VERSION 5.7 ;
  NOWIREEXTENSIONATPIN ON ;
  DIVIDERCHAR "/" ;
  BUSBITCHARS "[]" ;
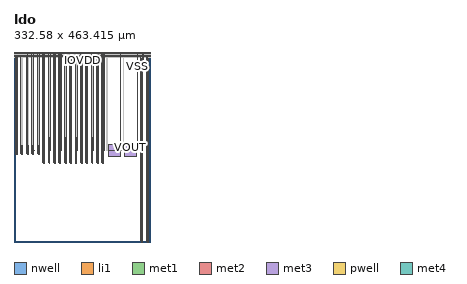
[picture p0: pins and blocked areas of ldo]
MACRO ldo
  CLASS BLOCK ;
  FOREIGN ldo ;
  ORIGIN 4.500 223.305 ;
  SIZE 332.580 BY 463.415 ;
  PIN IOVDD
    DIRECTION INOUT ;
    USE POWER ;
    ANTENNADIFFAREA 494.460388 ;
    PORT
      LAYER nwell ;
        RECT 40.880 -11.095 43.340 11.095 ;
        RECT 54.340 -11.095 56.800 11.095 ;
        RECT 67.800 -31.095 69.910 31.095 ;
        RECT 80.910 -31.095 83.020 31.095 ;
        RECT 94.020 -31.095 96.130 31.095 ;
        RECT 107.130 -31.095 109.240 31.095 ;
        RECT 120.240 -31.095 122.350 31.095 ;
        RECT 133.350 -31.095 135.460 31.095 ;
        RECT 146.460 -31.095 148.570 31.095 ;
        RECT 159.570 -31.095 161.680 31.095 ;
        RECT 172.680 -31.095 174.790 31.095 ;
        RECT 185.790 -31.095 187.900 31.095 ;
        RECT 198.900 -31.095 201.010 31.095 ;
        RECT 212.010 -31.095 214.120 31.095 ;
      LAYER li1 ;
        RECT 67.980 30.745 69.730 30.915 ;
        RECT 41.060 10.745 43.160 10.915 ;
        RECT 41.060 -7.685 41.230 10.745 ;
        RECT 38.880 -8.185 41.230 -7.685 ;
        RECT 41.060 -10.745 41.230 -8.185 ;
        RECT 42.420 -10.020 42.590 10.020 ;
        RECT 42.990 -10.745 43.160 10.745 ;
        RECT 54.520 10.745 56.620 10.915 ;
        RECT 54.520 -7.685 54.690 10.745 ;
        RECT 52.340 -8.185 54.690 -7.685 ;
        RECT 41.060 -10.915 43.160 -10.745 ;
        RECT 54.520 -10.745 54.690 -8.185 ;
        RECT 55.880 -10.020 56.050 10.020 ;
        RECT 56.450 -10.745 56.620 10.745 ;
        RECT 54.520 -10.915 56.620 -10.745 ;
        RECT 67.980 -27.685 68.150 30.745 ;
        RECT 65.800 -28.185 68.150 -27.685 ;
        RECT 67.980 -30.745 68.150 -28.185 ;
        RECT 68.990 -30.020 69.160 30.020 ;
        RECT 69.560 -30.745 69.730 30.745 ;
        RECT 81.090 30.745 82.840 30.915 ;
        RECT 81.090 -27.685 81.260 30.745 ;
        RECT 78.910 -28.185 81.260 -27.685 ;
        RECT 67.980 -30.915 69.730 -30.745 ;
        RECT 81.090 -30.745 81.260 -28.185 ;
        RECT 82.100 -30.020 82.270 30.020 ;
        RECT 82.670 -30.745 82.840 30.745 ;
        RECT 94.200 30.745 95.950 30.915 ;
        RECT 94.200 -27.685 94.370 30.745 ;
        RECT 92.020 -28.185 94.370 -27.685 ;
        RECT 81.090 -30.915 82.840 -30.745 ;
        RECT 94.200 -30.745 94.370 -28.185 ;
        RECT 95.210 -30.020 95.380 30.020 ;
        RECT 95.780 -30.745 95.950 30.745 ;
        RECT 107.310 30.745 109.060 30.915 ;
        RECT 107.310 -27.685 107.480 30.745 ;
        RECT 105.130 -28.185 107.480 -27.685 ;
        RECT 94.200 -30.915 95.950 -30.745 ;
        RECT 107.310 -30.745 107.480 -28.185 ;
        RECT 108.320 -30.020 108.490 30.020 ;
        RECT 108.890 -30.745 109.060 30.745 ;
        RECT 120.420 30.745 122.170 30.915 ;
        RECT 120.420 -27.685 120.590 30.745 ;
        RECT 118.240 -28.185 120.590 -27.685 ;
        RECT 107.310 -30.915 109.060 -30.745 ;
        RECT 120.420 -30.745 120.590 -28.185 ;
        RECT 121.430 -30.020 121.600 30.020 ;
        RECT 122.000 -30.745 122.170 30.745 ;
        RECT 133.530 30.745 135.280 30.915 ;
        RECT 133.530 -27.685 133.700 30.745 ;
        RECT 131.350 -28.185 133.700 -27.685 ;
        RECT 120.420 -30.915 122.170 -30.745 ;
        RECT 133.530 -30.745 133.700 -28.185 ;
        RECT 134.540 -30.020 134.710 30.020 ;
        RECT 135.110 -30.745 135.280 30.745 ;
        RECT 146.640 30.745 148.390 30.915 ;
        RECT 146.640 -27.685 146.810 30.745 ;
        RECT 144.460 -28.185 146.810 -27.685 ;
        RECT 133.530 -30.915 135.280 -30.745 ;
        RECT 146.640 -30.745 146.810 -28.185 ;
        RECT 147.650 -30.020 147.820 30.020 ;
        RECT 148.220 -30.745 148.390 30.745 ;
        RECT 159.750 30.745 161.500 30.915 ;
        RECT 159.750 -27.685 159.920 30.745 ;
        RECT 157.570 -28.185 159.920 -27.685 ;
        RECT 146.640 -30.915 148.390 -30.745 ;
        RECT 159.750 -30.745 159.920 -28.185 ;
        RECT 160.760 -30.020 160.930 30.020 ;
        RECT 161.330 -30.745 161.500 30.745 ;
        RECT 172.860 30.745 174.610 30.915 ;
        RECT 172.860 -27.685 173.030 30.745 ;
        RECT 170.680 -28.185 173.030 -27.685 ;
        RECT 159.750 -30.915 161.500 -30.745 ;
        RECT 172.860 -30.745 173.030 -28.185 ;
        RECT 173.870 -30.020 174.040 30.020 ;
        RECT 174.440 -30.745 174.610 30.745 ;
        RECT 185.970 30.745 187.720 30.915 ;
        RECT 185.970 -27.685 186.140 30.745 ;
        RECT 183.790 -28.185 186.140 -27.685 ;
        RECT 172.860 -30.915 174.610 -30.745 ;
        RECT 185.970 -30.745 186.140 -28.185 ;
        RECT 186.980 -30.020 187.150 30.020 ;
        RECT 187.550 -30.745 187.720 30.745 ;
        RECT 199.080 30.745 200.830 30.915 ;
        RECT 199.080 -27.685 199.250 30.745 ;
        RECT 196.900 -28.185 199.250 -27.685 ;
        RECT 185.970 -30.915 187.720 -30.745 ;
        RECT 199.080 -30.745 199.250 -28.185 ;
        RECT 200.090 -30.020 200.260 30.020 ;
        RECT 200.660 -30.745 200.830 30.745 ;
        RECT 212.190 30.745 213.940 30.915 ;
        RECT 212.190 -27.685 212.360 30.745 ;
        RECT 210.010 -28.185 212.360 -27.685 ;
        RECT 199.080 -30.915 200.830 -30.745 ;
        RECT 212.190 -30.745 212.360 -28.185 ;
        RECT 213.200 -30.020 213.370 30.020 ;
        RECT 213.770 -30.745 213.940 30.745 ;
        RECT 212.190 -30.915 213.940 -30.745 ;
      LAYER met1 ;
        RECT 42.390 0.200 42.620 10.000 ;
        RECT 55.850 0.200 56.080 10.000 ;
        RECT 68.960 0.200 69.190 30.000 ;
        RECT 82.070 0.200 82.300 30.000 ;
        RECT 95.180 0.200 95.410 30.000 ;
        RECT 108.290 0.200 108.520 30.000 ;
        RECT 121.400 0.200 121.630 30.000 ;
        RECT 134.510 0.200 134.740 30.000 ;
        RECT 147.620 0.200 147.850 30.000 ;
        RECT 160.730 0.200 160.960 30.000 ;
        RECT 173.840 0.200 174.070 30.000 ;
        RECT 186.950 0.200 187.180 30.000 ;
        RECT 200.060 0.200 200.290 30.000 ;
        RECT 213.170 0.200 213.400 30.000 ;
        RECT 42.390 -0.200 44.290 0.200 ;
        RECT 55.850 -0.200 57.750 0.200 ;
        RECT 68.960 -0.200 70.860 0.200 ;
        RECT 82.070 -0.200 83.970 0.200 ;
        RECT 95.180 -0.200 97.080 0.200 ;
        RECT 108.290 -0.200 110.190 0.200 ;
        RECT 121.400 -0.200 123.300 0.200 ;
        RECT 134.510 -0.200 136.410 0.200 ;
        RECT 147.620 -0.200 149.520 0.200 ;
        RECT 160.730 -0.200 162.630 0.200 ;
        RECT 173.840 -0.200 175.740 0.200 ;
        RECT 186.950 -0.200 188.850 0.200 ;
        RECT 200.060 -0.200 201.960 0.200 ;
        RECT 213.170 -0.200 215.070 0.200 ;
        RECT 38.930 -8.135 39.330 -7.735 ;
        RECT 42.390 -10.000 42.620 -0.200 ;
        RECT 52.390 -8.135 52.790 -7.735 ;
        RECT 55.850 -10.000 56.080 -0.200 ;
        RECT 65.850 -28.135 66.250 -27.735 ;
        RECT 68.960 -30.000 69.190 -0.200 ;
        RECT 78.960 -28.135 79.360 -27.735 ;
        RECT 82.070 -30.000 82.300 -0.200 ;
        RECT 92.070 -28.135 92.470 -27.735 ;
        RECT 95.180 -30.000 95.410 -0.200 ;
        RECT 105.180 -28.135 105.580 -27.735 ;
        RECT 108.290 -30.000 108.520 -0.200 ;
        RECT 118.290 -28.135 118.690 -27.735 ;
        RECT 121.400 -30.000 121.630 -0.200 ;
        RECT 131.400 -28.135 131.800 -27.735 ;
        RECT 134.510 -30.000 134.740 -0.200 ;
        RECT 144.510 -28.135 144.910 -27.735 ;
        RECT 147.620 -30.000 147.850 -0.200 ;
        RECT 157.620 -28.135 158.020 -27.735 ;
        RECT 160.730 -30.000 160.960 -0.200 ;
        RECT 170.730 -28.135 171.130 -27.735 ;
        RECT 173.840 -30.000 174.070 -0.200 ;
        RECT 183.840 -28.135 184.240 -27.735 ;
        RECT 186.950 -30.000 187.180 -0.200 ;
        RECT 196.950 -28.135 197.350 -27.735 ;
        RECT 200.060 -30.000 200.290 -0.200 ;
        RECT 210.060 -28.135 210.460 -27.735 ;
        RECT 213.170 -30.000 213.400 -0.200 ;
      LAYER met2 ;
        RECT 38.930 238.160 39.330 238.560 ;
        RECT 43.890 238.160 44.290 238.560 ;
        RECT 52.390 238.160 52.790 238.560 ;
        RECT 57.350 238.160 57.750 238.560 ;
        RECT 65.850 238.160 66.250 238.560 ;
        RECT 70.460 238.160 70.860 238.560 ;
        RECT 78.960 238.160 79.360 238.560 ;
        RECT 83.570 238.160 83.970 238.560 ;
        RECT 92.070 238.160 92.470 238.560 ;
        RECT 96.680 238.160 97.080 238.560 ;
        RECT 105.180 238.160 105.580 238.560 ;
        RECT 109.790 238.160 110.190 238.560 ;
        RECT 118.290 238.160 118.690 238.560 ;
        RECT 122.900 238.160 123.300 238.560 ;
        RECT 131.400 238.160 131.800 238.560 ;
        RECT 136.010 238.160 136.410 238.560 ;
        RECT 144.510 238.160 144.910 238.560 ;
        RECT 149.120 238.160 149.520 238.560 ;
        RECT 157.620 238.160 158.020 238.560 ;
        RECT 162.230 238.160 162.630 238.560 ;
        RECT 170.730 238.160 171.130 238.560 ;
        RECT 175.340 238.160 175.740 238.560 ;
        RECT 183.840 238.160 184.240 238.560 ;
        RECT 188.450 238.160 188.850 238.560 ;
        RECT 196.950 238.160 197.350 238.560 ;
        RECT 201.560 238.160 201.960 238.560 ;
        RECT 210.060 238.160 210.460 238.560 ;
        RECT 214.670 238.160 215.070 238.560 ;
        RECT 38.980 -7.735 39.280 238.160 ;
        RECT 43.940 0.200 44.240 238.160 ;
        RECT 43.890 -0.200 44.290 0.200 ;
        RECT 52.440 -7.735 52.740 238.160 ;
        RECT 57.400 0.200 57.700 238.160 ;
        RECT 57.350 -0.200 57.750 0.200 ;
        RECT 38.930 -8.135 39.330 -7.735 ;
        RECT 52.390 -8.135 52.790 -7.735 ;
        RECT 65.900 -27.735 66.200 238.160 ;
        RECT 70.510 0.200 70.810 238.160 ;
        RECT 70.460 -0.200 70.860 0.200 ;
        RECT 79.010 -27.735 79.310 238.160 ;
        RECT 83.620 0.200 83.920 238.160 ;
        RECT 83.570 -0.200 83.970 0.200 ;
        RECT 92.120 -27.735 92.420 238.160 ;
        RECT 96.730 0.200 97.030 238.160 ;
        RECT 96.680 -0.200 97.080 0.200 ;
        RECT 105.230 -27.735 105.530 238.160 ;
        RECT 109.840 0.200 110.140 238.160 ;
        RECT 109.790 -0.200 110.190 0.200 ;
        RECT 118.340 -27.735 118.640 238.160 ;
        RECT 122.950 0.200 123.250 238.160 ;
        RECT 122.900 -0.200 123.300 0.200 ;
        RECT 131.450 -27.735 131.750 238.160 ;
        RECT 136.060 0.200 136.360 238.160 ;
        RECT 136.010 -0.200 136.410 0.200 ;
        RECT 144.560 -27.735 144.860 238.160 ;
        RECT 149.170 0.200 149.470 238.160 ;
        RECT 149.120 -0.200 149.520 0.200 ;
        RECT 157.670 -27.735 157.970 238.160 ;
        RECT 162.280 0.200 162.580 238.160 ;
        RECT 162.230 -0.200 162.630 0.200 ;
        RECT 170.780 -27.735 171.080 238.160 ;
        RECT 175.390 0.200 175.690 238.160 ;
        RECT 175.340 -0.200 175.740 0.200 ;
        RECT 183.890 -27.735 184.190 238.160 ;
        RECT 188.500 0.200 188.800 238.160 ;
        RECT 188.450 -0.200 188.850 0.200 ;
        RECT 197.000 -27.735 197.300 238.160 ;
        RECT 201.610 0.200 201.910 238.160 ;
        RECT 201.560 -0.200 201.960 0.200 ;
        RECT 210.110 -27.735 210.410 238.160 ;
        RECT 214.720 0.200 215.020 238.160 ;
        RECT 214.670 -0.200 215.070 0.200 ;
        RECT 65.850 -28.135 66.250 -27.735 ;
        RECT 78.960 -28.135 79.360 -27.735 ;
        RECT 92.070 -28.135 92.470 -27.735 ;
        RECT 105.180 -28.135 105.580 -27.735 ;
        RECT 118.290 -28.135 118.690 -27.735 ;
        RECT 131.400 -28.135 131.800 -27.735 ;
        RECT 144.510 -28.135 144.910 -27.735 ;
        RECT 157.620 -28.135 158.020 -27.735 ;
        RECT 170.730 -28.135 171.130 -27.735 ;
        RECT 183.840 -28.135 184.240 -27.735 ;
        RECT 196.950 -28.135 197.350 -27.735 ;
        RECT 210.060 -28.135 210.460 -27.735 ;
      LAYER met3 ;
        RECT -4.500 238.110 328.080 238.610 ;
    END
  END IOVDD
  PIN VSS
    DIRECTION INOUT ;
    USE GROUND ;
    ANTENNADIFFAREA 332.556396 ;
    PORT
      LAYER pwell ;
        RECT 0.000 -9.050 2.960 9.050 ;
        RECT 13.960 -11.050 16.420 11.050 ;
        RECT 27.420 -11.050 29.880 11.050 ;
        RECT 306.440 -223.360 309.510 223.360 ;
        RECT 320.510 -223.360 323.580 223.360 ;
      LAYER li1 ;
        RECT 306.620 223.010 309.330 223.180 ;
        RECT 14.140 10.700 16.240 10.870 ;
        RECT 0.180 8.700 2.780 8.870 ;
        RECT 0.180 -5.640 0.350 8.700 ;
        RECT -2.000 -6.140 0.350 -5.640 ;
        RECT 0.180 -8.700 0.350 -6.140 ;
        RECT 2.040 -8.020 2.210 8.020 ;
        RECT 2.610 -8.700 2.780 8.700 ;
        RECT 14.140 -7.640 14.310 10.700 ;
        RECT 11.960 -8.140 14.310 -7.640 ;
        RECT 0.180 -8.870 2.780 -8.700 ;
        RECT 14.140 -10.700 14.310 -8.140 ;
        RECT 16.070 -10.700 16.240 10.700 ;
        RECT 27.600 10.700 29.700 10.870 ;
        RECT 27.600 -7.640 27.770 10.700 ;
        RECT 25.420 -8.140 27.770 -7.640 ;
        RECT 14.140 -10.870 16.240 -10.700 ;
        RECT 27.600 -10.700 27.770 -8.140 ;
        RECT 29.530 -10.700 29.700 10.700 ;
        RECT 27.600 -10.870 29.700 -10.700 ;
        RECT 306.620 -219.950 306.790 223.010 ;
        RECT 304.440 -220.450 306.790 -219.950 ;
        RECT 306.620 -223.010 306.790 -220.450 ;
        RECT 309.160 -223.010 309.330 223.010 ;
        RECT 320.690 223.010 323.400 223.180 ;
        RECT 320.690 -219.950 320.860 223.010 ;
        RECT 318.510 -220.450 320.860 -219.950 ;
        RECT 306.620 -223.180 309.330 -223.010 ;
        RECT 320.690 -223.010 320.860 -220.450 ;
        RECT 321.340 -222.530 322.750 -220.370 ;
        RECT 323.230 -223.010 323.400 223.010 ;
        RECT 320.690 -223.180 323.400 -223.010 ;
      LAYER met1 ;
        RECT 2.010 0.200 2.240 8.000 ;
        RECT 2.010 -0.200 3.910 0.200 ;
        RECT -1.950 -6.090 -1.550 -5.690 ;
        RECT 2.010 -8.000 2.240 -0.200 ;
        RECT 12.010 -8.090 12.410 -7.690 ;
        RECT 25.470 -8.090 25.870 -7.690 ;
        RECT 304.490 -220.400 304.890 -220.000 ;
        RECT 318.560 -220.400 318.960 -220.000 ;
        RECT 321.390 -222.155 322.700 -220.395 ;
        RECT 319.560 -222.500 322.700 -222.155 ;
        RECT 319.560 -222.555 322.045 -222.500 ;
      LAYER met2 ;
        RECT -1.950 230.660 -1.550 231.060 ;
        RECT 3.510 230.660 3.910 231.060 ;
        RECT 12.010 230.660 12.410 231.060 ;
        RECT 25.470 230.660 25.870 231.060 ;
        RECT 304.490 230.660 304.890 231.060 ;
        RECT 318.560 230.660 318.960 231.060 ;
        RECT 319.560 230.660 319.960 231.060 ;
        RECT -1.900 -5.690 -1.600 230.660 ;
        RECT 3.560 0.200 3.860 230.660 ;
        RECT 3.510 -0.200 3.910 0.200 ;
        RECT -1.950 -6.090 -1.550 -5.690 ;
        RECT 12.060 -7.690 12.360 230.660 ;
        RECT 25.520 -7.690 25.820 230.660 ;
        RECT 12.010 -8.090 12.410 -7.690 ;
        RECT 25.470 -8.090 25.870 -7.690 ;
        RECT 304.540 -220.000 304.840 230.660 ;
        RECT 318.610 -220.000 318.910 230.660 ;
        RECT 304.490 -220.400 304.890 -220.000 ;
        RECT 318.560 -220.400 318.960 -220.000 ;
        RECT 319.610 -222.155 319.910 230.660 ;
        RECT 319.560 -222.555 319.960 -222.155 ;
      LAYER met3 ;
        RECT -4.500 230.610 328.080 231.110 ;
    END
  END VSS
  PIN VREF
    DIRECTION INPUT ;
    USE SIGNAL ;
    ANTENNAGATEAREA 10.000000 ;
    PORT
      LAYER li1 ;
        RECT 28.400 10.190 28.900 10.360 ;
        RECT 28.400 -10.360 28.900 -10.190 ;
      LAYER met1 ;
        RECT 28.450 10.390 28.850 10.725 ;
        RECT 28.420 10.160 28.880 10.390 ;
        RECT 28.420 -10.390 28.880 -10.160 ;
        RECT 28.450 -10.725 28.850 -10.390 ;
      LAYER met2 ;
        RECT 28.450 236.660 28.850 237.060 ;
        RECT 28.500 10.675 28.800 236.660 ;
        RECT 28.450 10.275 28.850 10.675 ;
      LAYER met3 ;
        RECT -4.500 236.610 328.080 237.110 ;
    END
  END VREF
  PIN VOUT
    DIRECTION OUTPUT ;
    USE SIGNAL ;
    ANTENNADIFFAREA 208.799988 ;
    PORT
      LAYER li1 ;
        RECT 307.270 220.370 308.680 222.530 ;
        RECT 68.550 -30.020 68.720 30.020 ;
        RECT 81.660 -30.020 81.830 30.020 ;
        RECT 94.770 -30.020 94.940 30.020 ;
        RECT 107.880 -30.020 108.050 30.020 ;
        RECT 120.990 -30.020 121.160 30.020 ;
        RECT 134.100 -30.020 134.270 30.020 ;
        RECT 147.210 -30.020 147.380 30.020 ;
        RECT 160.320 -30.020 160.490 30.020 ;
        RECT 173.430 -30.020 173.600 30.020 ;
        RECT 186.540 -30.020 186.710 30.020 ;
        RECT 199.650 -30.020 199.820 30.020 ;
        RECT 212.760 -30.020 212.930 30.020 ;
      LAYER met1 ;
        RECT 307.975 222.500 310.460 222.555 ;
        RECT 307.320 222.155 310.460 222.500 ;
        RECT 307.320 220.395 308.630 222.155 ;
        RECT 68.520 0.200 68.750 30.000 ;
        RECT 81.630 0.200 81.860 30.000 ;
        RECT 94.740 0.200 94.970 30.000 ;
        RECT 107.850 0.200 108.080 30.000 ;
        RECT 120.960 0.200 121.190 30.000 ;
        RECT 134.070 0.200 134.300 30.000 ;
        RECT 147.180 0.200 147.410 30.000 ;
        RECT 160.290 0.200 160.520 30.000 ;
        RECT 173.400 0.200 173.630 30.000 ;
        RECT 186.510 0.200 186.740 30.000 ;
        RECT 199.620 0.200 199.850 30.000 ;
        RECT 212.730 0.200 212.960 30.000 ;
        RECT 66.850 -0.200 68.750 0.200 ;
        RECT 79.960 -0.200 81.860 0.200 ;
        RECT 93.070 -0.200 94.970 0.200 ;
        RECT 106.180 -0.200 108.080 0.200 ;
        RECT 119.290 -0.200 121.190 0.200 ;
        RECT 132.400 -0.200 134.300 0.200 ;
        RECT 145.510 -0.200 147.410 0.200 ;
        RECT 158.620 -0.200 160.520 0.200 ;
        RECT 171.730 -0.200 173.630 0.200 ;
        RECT 184.840 -0.200 186.740 0.200 ;
        RECT 197.950 -0.200 199.850 0.200 ;
        RECT 211.060 -0.200 212.960 0.200 ;
        RECT 68.520 -30.000 68.750 -0.200 ;
        RECT 81.630 -30.000 81.860 -0.200 ;
        RECT 94.740 -30.000 94.970 -0.200 ;
        RECT 107.850 -30.000 108.080 -0.200 ;
        RECT 120.960 -30.000 121.190 -0.200 ;
        RECT 134.070 -30.000 134.300 -0.200 ;
        RECT 147.180 -30.000 147.410 -0.200 ;
        RECT 160.290 -30.000 160.520 -0.200 ;
        RECT 173.400 -30.000 173.630 -0.200 ;
        RECT 186.510 -30.000 186.740 -0.200 ;
        RECT 199.620 -30.000 199.850 -0.200 ;
        RECT 212.730 -30.000 212.960 -0.200 ;
      LAYER met2 ;
        RECT 66.850 239.660 67.250 240.060 ;
        RECT 79.960 239.660 80.360 240.060 ;
        RECT 93.070 239.660 93.470 240.060 ;
        RECT 106.180 239.660 106.580 240.060 ;
        RECT 119.290 239.660 119.690 240.060 ;
        RECT 132.400 239.660 132.800 240.060 ;
        RECT 145.510 239.660 145.910 240.060 ;
        RECT 158.620 239.660 159.020 240.060 ;
        RECT 171.730 239.660 172.130 240.060 ;
        RECT 184.840 239.660 185.240 240.060 ;
        RECT 197.950 239.660 198.350 240.060 ;
        RECT 211.060 239.660 211.460 240.060 ;
        RECT 256.080 239.660 256.480 240.060 ;
        RECT 296.740 239.660 297.140 240.060 ;
        RECT 310.060 239.660 310.460 240.060 ;
        RECT 66.900 0.200 67.200 239.660 ;
        RECT 80.010 0.200 80.310 239.660 ;
        RECT 93.120 0.200 93.420 239.660 ;
        RECT 106.230 0.200 106.530 239.660 ;
        RECT 119.340 0.200 119.640 239.660 ;
        RECT 132.450 0.200 132.750 239.660 ;
        RECT 145.560 0.200 145.860 239.660 ;
        RECT 158.670 0.200 158.970 239.660 ;
        RECT 171.780 0.200 172.080 239.660 ;
        RECT 184.890 0.200 185.190 239.660 ;
        RECT 198.000 0.200 198.300 239.660 ;
        RECT 211.110 0.200 211.410 239.660 ;
        RECT 256.130 0.200 256.430 239.660 ;
        RECT 296.790 0.200 297.090 239.660 ;
        RECT 310.110 222.555 310.410 239.660 ;
        RECT 310.060 222.155 310.460 222.555 ;
        RECT 66.850 -0.200 67.250 0.200 ;
        RECT 79.960 -0.200 80.360 0.200 ;
        RECT 93.070 -0.200 93.470 0.200 ;
        RECT 106.180 -0.200 106.580 0.200 ;
        RECT 119.290 -0.200 119.690 0.200 ;
        RECT 132.400 -0.200 132.800 0.200 ;
        RECT 145.510 -0.200 145.910 0.200 ;
        RECT 158.620 -0.200 159.020 0.200 ;
        RECT 171.730 -0.200 172.130 0.200 ;
        RECT 184.840 -0.200 185.240 0.200 ;
        RECT 197.950 -0.200 198.350 0.200 ;
        RECT 211.060 -0.200 211.460 0.200 ;
        RECT 256.080 -0.200 256.480 0.200 ;
        RECT 296.740 -0.200 297.140 0.200 ;
      LAYER met3 ;
        RECT -4.500 239.610 328.080 240.110 ;
        RECT 225.120 0.250 254.780 13.950 ;
        RECT 265.780 0.250 295.440 13.950 ;
        RECT 225.120 -0.250 256.880 0.250 ;
        RECT 265.780 -0.250 297.540 0.250 ;
        RECT 225.120 -13.950 254.780 -0.250 ;
        RECT 265.780 -13.950 295.440 -0.250 ;
      LAYER met4 ;
        RECT 254.280 -13.890 254.760 13.890 ;
        RECT 294.940 -13.890 295.420 13.890 ;
    END
  END VOUT
  PIN VBIAS
    DIRECTION INPUT ;
    USE SIGNAL ;
    ANTENNAGATEAREA 16.000000 ;
    PORT
      LAYER li1 ;
        RECT 0.980 8.190 1.980 8.360 ;
        RECT 0.980 -8.360 1.980 -8.190 ;
      LAYER met1 ;
        RECT 1.280 8.390 1.680 8.725 ;
        RECT 1.000 8.160 1.960 8.390 ;
        RECT 1.000 -8.390 1.960 -8.160 ;
        RECT 1.280 -8.725 1.680 -8.390 ;
      LAYER met2 ;
        RECT 1.280 229.160 1.680 229.560 ;
        RECT 1.330 8.675 1.630 229.160 ;
        RECT 1.280 8.275 1.680 8.675 ;
      LAYER met3 ;
        RECT -4.500 229.110 328.080 229.610 ;
    END
  END VBIAS
  OBS
      LAYER li1 ;
        RECT 321.340 220.370 322.750 222.530 ;
        RECT 68.690 30.235 69.020 30.405 ;
        RECT 81.800 30.235 82.130 30.405 ;
        RECT 94.910 30.235 95.240 30.405 ;
        RECT 108.020 30.235 108.350 30.405 ;
        RECT 121.130 30.235 121.460 30.405 ;
        RECT 134.240 30.235 134.570 30.405 ;
        RECT 147.350 30.235 147.680 30.405 ;
        RECT 160.460 30.235 160.790 30.405 ;
        RECT 173.570 30.235 173.900 30.405 ;
        RECT 186.680 30.235 187.010 30.405 ;
        RECT 199.790 30.235 200.120 30.405 ;
        RECT 212.900 30.235 213.230 30.405 ;
        RECT 14.940 10.190 15.440 10.360 ;
        RECT 41.860 10.235 42.360 10.405 ;
        RECT 55.320 10.235 55.820 10.405 ;
        RECT 0.750 -8.020 0.920 8.020 ;
        RECT 14.710 -10.020 14.880 10.020 ;
        RECT 15.500 -10.020 15.670 10.020 ;
        RECT 28.170 -10.020 28.340 10.020 ;
        RECT 28.960 -10.020 29.130 10.020 ;
        RECT 41.630 -10.020 41.800 10.020 ;
        RECT 55.090 -10.020 55.260 10.020 ;
        RECT 14.940 -10.360 15.440 -10.190 ;
        RECT 41.860 -10.405 42.360 -10.235 ;
        RECT 55.320 -10.405 55.820 -10.235 ;
        RECT 68.690 -30.405 69.020 -30.235 ;
        RECT 81.800 -30.405 82.130 -30.235 ;
        RECT 94.910 -30.405 95.240 -30.235 ;
        RECT 108.020 -30.405 108.350 -30.235 ;
        RECT 121.130 -30.405 121.460 -30.235 ;
        RECT 134.240 -30.405 134.570 -30.235 ;
        RECT 147.350 -30.405 147.680 -30.235 ;
        RECT 160.460 -30.405 160.790 -30.235 ;
        RECT 173.570 -30.405 173.900 -30.235 ;
        RECT 186.680 -30.405 187.010 -30.235 ;
        RECT 199.790 -30.405 200.120 -30.235 ;
        RECT 212.900 -30.405 213.230 -30.235 ;
        RECT 307.270 -222.530 308.680 -220.370 ;
      LAYER met1 ;
        RECT 322.045 222.500 324.530 222.555 ;
        RECT 321.390 222.155 324.530 222.500 ;
        RECT 321.390 220.395 322.700 222.155 ;
        RECT 68.655 30.270 69.055 30.770 ;
        RECT 81.765 30.270 82.165 30.770 ;
        RECT 94.875 30.270 95.275 30.770 ;
        RECT 107.985 30.270 108.385 30.770 ;
        RECT 121.095 30.270 121.495 30.770 ;
        RECT 134.205 30.270 134.605 30.770 ;
        RECT 147.315 30.270 147.715 30.770 ;
        RECT 160.425 30.270 160.825 30.770 ;
        RECT 173.535 30.270 173.935 30.770 ;
        RECT 186.645 30.270 187.045 30.770 ;
        RECT 199.755 30.270 200.155 30.770 ;
        RECT 212.865 30.270 213.265 30.770 ;
        RECT 68.710 30.205 69.000 30.270 ;
        RECT 81.820 30.205 82.110 30.270 ;
        RECT 94.930 30.205 95.220 30.270 ;
        RECT 108.040 30.205 108.330 30.270 ;
        RECT 121.150 30.205 121.440 30.270 ;
        RECT 134.260 30.205 134.550 30.270 ;
        RECT 147.370 30.205 147.660 30.270 ;
        RECT 160.480 30.205 160.770 30.270 ;
        RECT 173.590 30.205 173.880 30.270 ;
        RECT 186.700 30.205 186.990 30.270 ;
        RECT 199.810 30.205 200.100 30.270 ;
        RECT 212.920 30.205 213.210 30.270 ;
        RECT 14.990 10.390 15.390 10.725 ;
        RECT 41.910 10.435 42.310 10.770 ;
        RECT 55.370 10.435 55.770 10.770 ;
        RECT 14.960 10.160 15.420 10.390 ;
        RECT 41.880 10.205 42.340 10.435 ;
        RECT 55.340 10.205 55.800 10.435 ;
        RECT 0.720 0.200 0.950 8.000 ;
        RECT 14.680 0.200 14.910 10.000 ;
        RECT -0.950 -0.200 0.950 0.200 ;
        RECT 13.010 -0.200 14.910 0.200 ;
        RECT 0.720 -8.000 0.950 -0.200 ;
        RECT 14.680 -10.000 14.910 -0.200 ;
        RECT 15.470 0.200 15.700 10.000 ;
        RECT 28.140 0.200 28.370 10.000 ;
        RECT 15.470 -0.200 17.370 0.200 ;
        RECT 26.470 -0.200 28.370 0.200 ;
        RECT 15.470 -10.000 15.700 -0.200 ;
        RECT 28.140 -10.000 28.370 -0.200 ;
        RECT 28.930 0.200 29.160 10.000 ;
        RECT 41.600 0.200 41.830 10.000 ;
        RECT 55.060 0.200 55.290 10.000 ;
        RECT 28.930 -0.200 30.830 0.200 ;
        RECT 39.930 -0.200 41.830 0.200 ;
        RECT 53.390 -0.200 55.290 0.200 ;
        RECT 28.930 -10.000 29.160 -0.200 ;
        RECT 41.600 -10.000 41.830 -0.200 ;
        RECT 55.060 -10.000 55.290 -0.200 ;
        RECT 14.960 -10.390 15.420 -10.160 ;
        RECT 14.990 -10.725 15.390 -10.390 ;
        RECT 41.880 -10.435 42.340 -10.205 ;
        RECT 55.340 -10.435 55.800 -10.205 ;
        RECT 41.910 -10.770 42.310 -10.435 ;
        RECT 55.370 -10.770 55.770 -10.435 ;
        RECT 68.710 -30.270 69.000 -30.205 ;
        RECT 81.820 -30.270 82.110 -30.205 ;
        RECT 94.930 -30.270 95.220 -30.205 ;
        RECT 108.040 -30.270 108.330 -30.205 ;
        RECT 121.150 -30.270 121.440 -30.205 ;
        RECT 134.260 -30.270 134.550 -30.205 ;
        RECT 147.370 -30.270 147.660 -30.205 ;
        RECT 160.480 -30.270 160.770 -30.205 ;
        RECT 173.590 -30.270 173.880 -30.205 ;
        RECT 186.700 -30.270 186.990 -30.205 ;
        RECT 199.810 -30.270 200.100 -30.205 ;
        RECT 212.920 -30.270 213.210 -30.205 ;
        RECT 68.655 -30.770 69.055 -30.270 ;
        RECT 81.765 -30.770 82.165 -30.270 ;
        RECT 94.875 -30.770 95.275 -30.270 ;
        RECT 107.985 -30.770 108.385 -30.270 ;
        RECT 121.095 -30.770 121.495 -30.270 ;
        RECT 134.205 -30.770 134.605 -30.270 ;
        RECT 147.315 -30.770 147.715 -30.270 ;
        RECT 160.425 -30.770 160.825 -30.270 ;
        RECT 173.535 -30.770 173.935 -30.270 ;
        RECT 186.645 -30.770 187.045 -30.270 ;
        RECT 199.755 -30.770 200.155 -30.270 ;
        RECT 212.865 -30.770 213.265 -30.270 ;
        RECT 307.320 -222.155 308.630 -220.395 ;
        RECT 305.490 -222.500 308.630 -222.155 ;
        RECT 305.490 -222.555 307.975 -222.500 ;
      LAYER met2 ;
        RECT 26.470 235.160 26.870 235.560 ;
        RECT 53.390 235.160 53.790 235.560 ;
        RECT 68.655 235.160 69.055 235.560 ;
        RECT 81.765 235.160 82.165 235.560 ;
        RECT 94.875 235.160 95.275 235.560 ;
        RECT 107.985 235.160 108.385 235.560 ;
        RECT 121.095 235.160 121.495 235.560 ;
        RECT 134.205 235.160 134.605 235.560 ;
        RECT 147.315 235.160 147.715 235.560 ;
        RECT 160.425 235.160 160.825 235.560 ;
        RECT 173.535 235.160 173.935 235.560 ;
        RECT 186.645 235.160 187.045 235.560 ;
        RECT 199.755 235.160 200.155 235.560 ;
        RECT 212.865 235.160 213.265 235.560 ;
        RECT 222.220 235.160 222.620 235.560 ;
        RECT 262.880 235.160 263.280 235.560 ;
        RECT 14.990 233.660 15.390 234.060 ;
        RECT 13.010 232.160 13.410 232.560 ;
        RECT -0.950 227.660 -0.550 228.060 ;
        RECT -0.900 0.200 -0.600 227.660 ;
        RECT 13.060 0.200 13.360 232.160 ;
        RECT 15.040 10.675 15.340 233.660 ;
        RECT 16.970 227.660 17.370 228.060 ;
        RECT 14.990 10.275 15.390 10.675 ;
        RECT 17.020 0.200 17.320 227.660 ;
        RECT 26.520 0.200 26.820 235.160 ;
        RECT 39.930 232.160 40.330 232.560 ;
        RECT 41.910 232.160 42.310 232.560 ;
        RECT 30.430 227.660 30.830 228.060 ;
        RECT 30.480 0.200 30.780 227.660 ;
        RECT 39.980 0.200 40.280 232.160 ;
        RECT 41.960 10.720 42.260 232.160 ;
        RECT 41.910 10.320 42.310 10.720 ;
        RECT 53.440 0.200 53.740 235.160 ;
        RECT 55.370 232.160 55.770 232.560 ;
        RECT 55.420 10.720 55.720 232.160 ;
        RECT 68.705 30.720 69.005 235.160 ;
        RECT 81.815 30.720 82.115 235.160 ;
        RECT 94.925 30.720 95.225 235.160 ;
        RECT 108.035 30.720 108.335 235.160 ;
        RECT 121.145 30.720 121.445 235.160 ;
        RECT 134.255 30.720 134.555 235.160 ;
        RECT 147.365 30.720 147.665 235.160 ;
        RECT 160.475 30.720 160.775 235.160 ;
        RECT 173.585 30.720 173.885 235.160 ;
        RECT 186.695 30.720 186.995 235.160 ;
        RECT 199.805 30.720 200.105 235.160 ;
        RECT 212.915 30.720 213.215 235.160 ;
        RECT 68.655 30.320 69.055 30.720 ;
        RECT 81.765 30.320 82.165 30.720 ;
        RECT 94.875 30.320 95.275 30.720 ;
        RECT 107.985 30.320 108.385 30.720 ;
        RECT 121.095 30.320 121.495 30.720 ;
        RECT 134.205 30.320 134.605 30.720 ;
        RECT 147.315 30.320 147.715 30.720 ;
        RECT 160.425 30.320 160.825 30.720 ;
        RECT 173.535 30.320 173.935 30.720 ;
        RECT 186.645 30.320 187.045 30.720 ;
        RECT 199.755 30.320 200.155 30.720 ;
        RECT 212.865 30.320 213.265 30.720 ;
        RECT 55.370 10.320 55.770 10.720 ;
        RECT 222.270 0.200 222.570 235.160 ;
        RECT 262.930 0.200 263.230 235.160 ;
        RECT 305.490 233.660 305.890 234.060 ;
        RECT 324.130 233.660 324.530 234.060 ;
        RECT -0.950 -0.200 -0.550 0.200 ;
        RECT 13.010 -0.200 13.410 0.200 ;
        RECT 16.970 -0.200 17.370 0.200 ;
        RECT 26.470 -0.200 26.870 0.200 ;
        RECT 30.430 -0.200 30.830 0.200 ;
        RECT 39.930 -0.200 40.330 0.200 ;
        RECT 53.390 -0.200 53.790 0.200 ;
        RECT 222.220 -0.200 222.620 0.200 ;
        RECT 262.880 -0.200 263.280 0.200 ;
        RECT 305.540 -222.155 305.840 233.660 ;
        RECT 324.180 222.555 324.480 233.660 ;
        RECT 324.130 222.155 324.530 222.555 ;
        RECT 305.490 -222.555 305.890 -222.155 ;
      LAYER met3 ;
        RECT -4.500 235.110 328.080 235.610 ;
        RECT -4.500 233.610 328.080 234.110 ;
        RECT -4.500 232.110 328.080 232.610 ;
        RECT -4.500 227.610 328.080 228.110 ;
        RECT 221.220 -0.200 222.820 0.200 ;
        RECT 261.880 -0.200 263.480 0.200 ;
      LAYER met4 ;
        RECT 225.515 0.200 252.625 13.555 ;
        RECT 266.175 0.200 293.285 13.555 ;
        RECT 221.120 -0.200 252.625 0.200 ;
        RECT 261.780 -0.200 293.285 0.200 ;
        RECT 225.515 -13.555 252.625 -0.200 ;
        RECT 266.175 -13.555 293.285 -0.200 ;
  END
END ldo
END LIBRARY

